VERSION 5.8 ;
BUSBITCHARS "[]" ;
DIVIDERCHAR "/" ;
UNITS
    DATABASE MICRONS 1000 ;
END UNITS

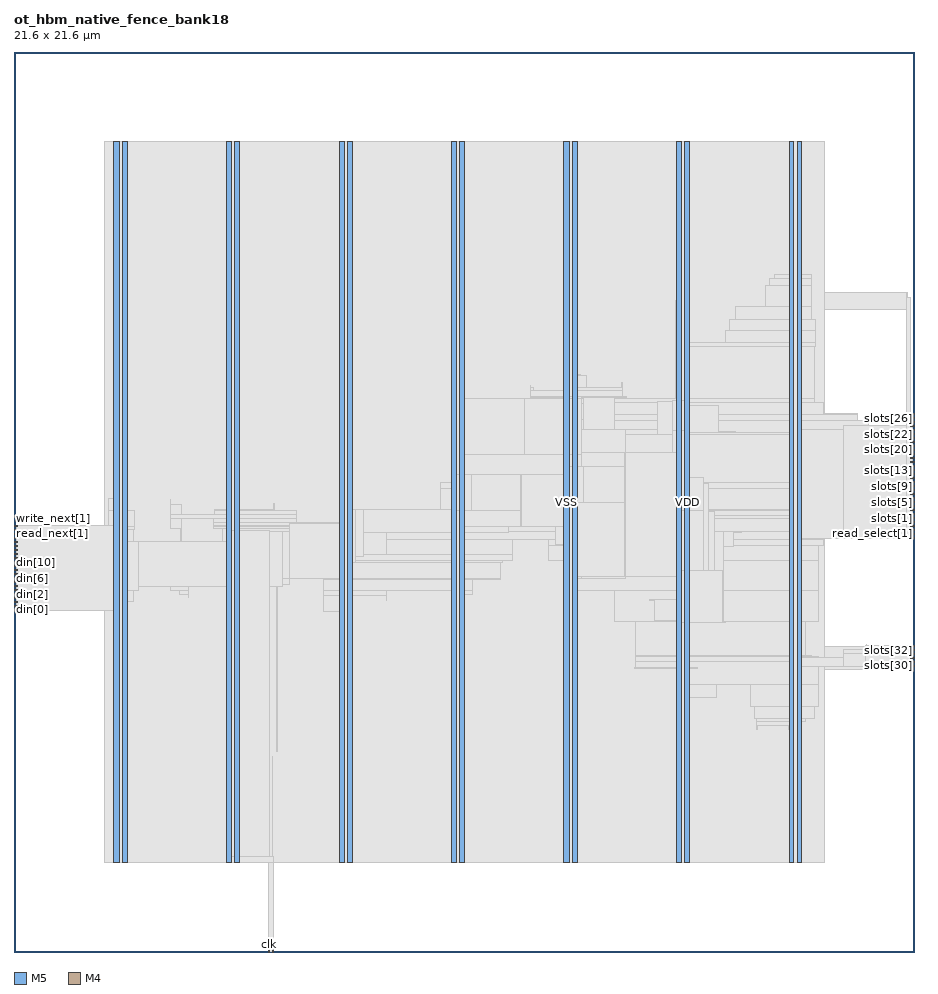
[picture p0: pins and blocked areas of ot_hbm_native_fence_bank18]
MACRO ot_hbm_native_fence_bank18
  FOREIGN ot_hbm_native_fence_bank18 0 0 ;
  CLASS BLOCK ;
  SIZE 21.6 BY 21.6 ;
  PIN clk
    DIRECTION INPUT ;
    USE SIGNAL ;
    PORT
      LAYER M5 ;
        RECT  6.096 0 6.12 0.084 ;
    END
  END clk
  PIN din[0]
    DIRECTION INPUT ;
    USE SIGNAL ;
    PORT
      LAYER M4 ;
        RECT  0 8.208 0.084 8.232 ;
    END
  END din[0]
  PIN din[10]
    DIRECTION INPUT ;
    USE SIGNAL ;
    PORT
      LAYER M4 ;
        RECT  0 9.168 0.084 9.192 ;
    END
  END din[10]
  PIN din[11]
    DIRECTION INPUT ;
    USE SIGNAL ;
    PORT
      LAYER M4 ;
        RECT  0 9.264 0.084 9.288 ;
    END
  END din[11]
  PIN din[12]
    DIRECTION INPUT ;
    USE SIGNAL ;
    PORT
      LAYER M4 ;
        RECT  0 9.36 0.084 9.384 ;
    END
  END din[12]
  PIN din[13]
    DIRECTION INPUT ;
    USE SIGNAL ;
    PORT
      LAYER M4 ;
        RECT  0 9.456 0.084 9.48 ;
    END
  END din[13]
  PIN din[14]
    DIRECTION INPUT ;
    USE SIGNAL ;
    PORT
      LAYER M4 ;
        RECT  0 9.552 0.084 9.576 ;
    END
  END din[14]
  PIN din[15]
    DIRECTION INPUT ;
    USE SIGNAL ;
    PORT
      LAYER M4 ;
        RECT  0 9.648 0.084 9.672 ;
    END
  END din[15]
  PIN din[16]
    DIRECTION INPUT ;
    USE SIGNAL ;
    PORT
      LAYER M4 ;
        RECT  0 9.744 0.084 9.768 ;
    END
  END din[16]
  PIN din[17]
    DIRECTION INPUT ;
    USE SIGNAL ;
    PORT
      LAYER M4 ;
        RECT  0 9.84 0.084 9.864 ;
    END
  END din[17]
  PIN din[1]
    DIRECTION INPUT ;
    USE SIGNAL ;
    PORT
      LAYER M4 ;
        RECT  0 8.304 0.084 8.328 ;
    END
  END din[1]
  PIN din[2]
    DIRECTION INPUT ;
    USE SIGNAL ;
    PORT
      LAYER M4 ;
        RECT  0 8.4 0.084 8.424 ;
    END
  END din[2]
  PIN din[3]
    DIRECTION INPUT ;
    USE SIGNAL ;
    PORT
      LAYER M4 ;
        RECT  0 8.496 0.084 8.52 ;
    END
  END din[3]
  PIN din[4]
    DIRECTION INPUT ;
    USE SIGNAL ;
    PORT
      LAYER M4 ;
        RECT  0 8.592 0.084 8.616 ;
    END
  END din[4]
  PIN din[5]
    DIRECTION INPUT ;
    USE SIGNAL ;
    PORT
      LAYER M4 ;
        RECT  0 8.688 0.084 8.712 ;
    END
  END din[5]
  PIN din[6]
    DIRECTION INPUT ;
    USE SIGNAL ;
    PORT
      LAYER M4 ;
        RECT  0 8.784 0.084 8.808 ;
    END
  END din[6]
  PIN din[7]
    DIRECTION INPUT ;
    USE SIGNAL ;
    PORT
      LAYER M4 ;
        RECT  0 8.88 0.084 8.904 ;
    END
  END din[7]
  PIN din[8]
    DIRECTION INPUT ;
    USE SIGNAL ;
    PORT
      LAYER M4 ;
        RECT  0 8.976 0.084 9 ;
    END
  END din[8]
  PIN din[9]
    DIRECTION INPUT ;
    USE SIGNAL ;
    PORT
      LAYER M4 ;
        RECT  0 9.072 0.084 9.096 ;
    END
  END din[9]
  PIN read_next[0]
    DIRECTION INPUT ;
    USE SIGNAL ;
    PORT
      LAYER M4 ;
        RECT  0 9.936 0.084 9.96 ;
    END
  END read_next[0]
  PIN read_next[1]
    DIRECTION INPUT ;
    USE SIGNAL ;
    PORT
      LAYER M4 ;
        RECT  0 10.032 0.084 10.056 ;
    END
  END read_next[1]
  PIN read_select[0]
    DIRECTION OUTPUT ;
    USE SIGNAL ;
    PORT
      LAYER M4 ;
        RECT  21.516 9.936 21.6 9.96 ;
    END
  END read_select[0]
  PIN read_select[1]
    DIRECTION OUTPUT ;
    USE SIGNAL ;
    PORT
      LAYER M4 ;
        RECT  21.516 10.032 21.6 10.056 ;
    END
  END read_select[1]
  PIN rst_n
    DIRECTION INPUT ;
    USE SIGNAL ;
    PORT
      LAYER M5 ;
        RECT  6.192 0 6.216 0.084 ;
    END
  END rst_n
  PIN slots[0]
    DIRECTION OUTPUT ;
    USE SIGNAL ;
    PORT
      LAYER M4 ;
        RECT  21.516 10.128 21.6 10.152 ;
    END
  END slots[0]
  PIN slots[10]
    DIRECTION OUTPUT ;
    USE SIGNAL ;
    PORT
      LAYER M4 ;
        RECT  21.516 11.088 21.6 11.112 ;
    END
  END slots[10]
  PIN slots[11]
    DIRECTION OUTPUT ;
    USE SIGNAL ;
    PORT
      LAYER M4 ;
        RECT  21.516 11.184 21.6 11.208 ;
    END
  END slots[11]
  PIN slots[12]
    DIRECTION OUTPUT ;
    USE SIGNAL ;
    PORT
      LAYER M4 ;
        RECT  21.516 11.28 21.6 11.304 ;
    END
  END slots[12]
  PIN slots[13]
    DIRECTION OUTPUT ;
    USE SIGNAL ;
    PORT
      LAYER M4 ;
        RECT  21.516 11.376 21.6 11.4 ;
    END
  END slots[13]
  PIN slots[14]
    DIRECTION OUTPUT ;
    USE SIGNAL ;
    PORT
      LAYER M4 ;
        RECT  21.516 11.472 21.6 11.496 ;
    END
  END slots[14]
  PIN slots[15]
    DIRECTION OUTPUT ;
    USE SIGNAL ;
    PORT
      LAYER M4 ;
        RECT  21.516 11.568 21.6 11.592 ;
    END
  END slots[15]
  PIN slots[16]
    DIRECTION OUTPUT ;
    USE SIGNAL ;
    PORT
      LAYER M4 ;
        RECT  21.516 11.664 21.6 11.688 ;
    END
  END slots[16]
  PIN slots[17]
    DIRECTION OUTPUT ;
    USE SIGNAL ;
    PORT
      LAYER M4 ;
        RECT  21.516 11.76 21.6 11.784 ;
    END
  END slots[17]
  PIN slots[18]
    DIRECTION OUTPUT ;
    USE SIGNAL ;
    PORT
      LAYER M4 ;
        RECT  21.516 11.856 21.6 11.88 ;
    END
  END slots[18]
  PIN slots[19]
    DIRECTION OUTPUT ;
    USE SIGNAL ;
    PORT
      LAYER M4 ;
        RECT  21.516 11.952 21.6 11.976 ;
    END
  END slots[19]
  PIN slots[1]
    DIRECTION OUTPUT ;
    USE SIGNAL ;
    PORT
      LAYER M4 ;
        RECT  21.516 10.224 21.6 10.248 ;
    END
  END slots[1]
  PIN slots[20]
    DIRECTION OUTPUT ;
    USE SIGNAL ;
    PORT
      LAYER M4 ;
        RECT  21.516 12.048 21.6 12.072 ;
    END
  END slots[20]
  PIN slots[21]
    DIRECTION OUTPUT ;
    USE SIGNAL ;
    PORT
      LAYER M4 ;
        RECT  21.516 12.144 21.6 12.168 ;
    END
  END slots[21]
  PIN slots[22]
    DIRECTION OUTPUT ;
    USE SIGNAL ;
    PORT
      LAYER M4 ;
        RECT  21.516 12.24 21.6 12.264 ;
    END
  END slots[22]
  PIN slots[23]
    DIRECTION OUTPUT ;
    USE SIGNAL ;
    PORT
      LAYER M4 ;
        RECT  21.516 12.336 21.6 12.36 ;
    END
  END slots[23]
  PIN slots[24]
    DIRECTION OUTPUT ;
    USE SIGNAL ;
    PORT
      LAYER M4 ;
        RECT  21.516 12.432 21.6 12.456 ;
    END
  END slots[24]
  PIN slots[25]
    DIRECTION OUTPUT ;
    USE SIGNAL ;
    PORT
      LAYER M4 ;
        RECT  21.516 12.528 21.6 12.552 ;
    END
  END slots[25]
  PIN slots[26]
    DIRECTION OUTPUT ;
    USE SIGNAL ;
    PORT
      LAYER M4 ;
        RECT  21.516 12.624 21.6 12.648 ;
    END
  END slots[26]
  PIN slots[27]
    DIRECTION OUTPUT ;
    USE SIGNAL ;
    PORT
      LAYER M4 ;
        RECT  21.516 12.72 21.6 12.744 ;
    END
  END slots[27]
  PIN slots[28]
    DIRECTION OUTPUT ;
    USE SIGNAL ;
    PORT
      LAYER M4 ;
        RECT  21.516 12.816 21.6 12.84 ;
    END
  END slots[28]
  PIN slots[29]
    DIRECTION OUTPUT ;
    USE SIGNAL ;
    PORT
      LAYER M4 ;
        RECT  21.516 12.912 21.6 12.936 ;
    END
  END slots[29]
  PIN slots[2]
    DIRECTION OUTPUT ;
    USE SIGNAL ;
    PORT
      LAYER M4 ;
        RECT  21.516 10.32 21.6 10.344 ;
    END
  END slots[2]
  PIN slots[30]
    DIRECTION OUTPUT ;
    USE SIGNAL ;
    PORT
      LAYER M4 ;
        RECT  21.516 6.864 21.6 6.888 ;
    END
  END slots[30]
  PIN slots[31]
    DIRECTION OUTPUT ;
    USE SIGNAL ;
    PORT
      LAYER M4 ;
        RECT  21.516 6.96 21.6 6.984 ;
    END
  END slots[31]
  PIN slots[32]
    DIRECTION OUTPUT ;
    USE SIGNAL ;
    PORT
      LAYER M4 ;
        RECT  21.516 7.056 21.6 7.08 ;
    END
  END slots[32]
  PIN slots[33]
    DIRECTION OUTPUT ;
    USE SIGNAL ;
    PORT
      LAYER M4 ;
        RECT  21.516 7.152 21.6 7.176 ;
    END
  END slots[33]
  PIN slots[34]
    DIRECTION OUTPUT ;
    USE SIGNAL ;
    PORT
      LAYER M4 ;
        RECT  21.516 7.248 21.6 7.272 ;
    END
  END slots[34]
  PIN slots[35]
    DIRECTION OUTPUT ;
    USE SIGNAL ;
    PORT
      LAYER M4 ;
        RECT  21.516 7.344 21.6 7.368 ;
    END
  END slots[35]
  PIN slots[3]
    DIRECTION OUTPUT ;
    USE SIGNAL ;
    PORT
      LAYER M4 ;
        RECT  21.516 10.416 21.6 10.44 ;
    END
  END slots[3]
  PIN slots[4]
    DIRECTION OUTPUT ;
    USE SIGNAL ;
    PORT
      LAYER M4 ;
        RECT  21.516 10.512 21.6 10.536 ;
    END
  END slots[4]
  PIN slots[5]
    DIRECTION OUTPUT ;
    USE SIGNAL ;
    PORT
      LAYER M4 ;
        RECT  21.516 10.608 21.6 10.632 ;
    END
  END slots[5]
  PIN slots[6]
    DIRECTION OUTPUT ;
    USE SIGNAL ;
    PORT
      LAYER M4 ;
        RECT  21.516 10.704 21.6 10.728 ;
    END
  END slots[6]
  PIN slots[7]
    DIRECTION OUTPUT ;
    USE SIGNAL ;
    PORT
      LAYER M4 ;
        RECT  21.516 10.8 21.6 10.824 ;
    END
  END slots[7]
  PIN slots[8]
    DIRECTION OUTPUT ;
    USE SIGNAL ;
    PORT
      LAYER M4 ;
        RECT  21.516 10.896 21.6 10.92 ;
    END
  END slots[8]
  PIN slots[9]
    DIRECTION OUTPUT ;
    USE SIGNAL ;
    PORT
      LAYER M4 ;
        RECT  21.516 10.992 21.6 11.016 ;
    END
  END slots[9]
  PIN write_next[0]
    DIRECTION INPUT ;
    USE SIGNAL ;
    PORT
      LAYER M4 ;
        RECT  0 10.128 0.084 10.152 ;
    END
  END write_next[0]
  PIN write_next[1]
    DIRECTION INPUT ;
    USE SIGNAL ;
    PORT
      LAYER M4 ;
        RECT  0 10.224 0.084 10.248 ;
    END
  END write_next[1]
  PIN VDD
    DIRECTION INOUT ;
    USE POWER ;
    PORT
      LAYER M5 ;
        RECT  18.792 2.151 18.912 19.449 ;
        RECT  16.092 2.151 16.212 19.449 ;
        RECT  13.392 2.151 13.512 19.449 ;
        RECT  10.692 2.151 10.812 19.449 ;
        RECT  7.992 2.151 8.112 19.449 ;
        RECT  5.292 2.151 5.412 19.449 ;
        RECT  2.592 2.151 2.712 19.449 ;
    END
  END VDD
  PIN VSS
    DIRECTION INOUT ;
    USE GROUND ;
    PORT
      LAYER M5 ;
        RECT  18.6 2.137 18.72 19.463 ;
        RECT  15.9 2.137 16.02 19.463 ;
        RECT  13.2 2.137 13.32 19.463 ;
        RECT  10.5 2.137 10.62 19.463 ;
        RECT  7.8 2.137 7.92 19.463 ;
        RECT  5.1 2.137 5.22 19.463 ;
        RECT  2.4 2.137 2.52 19.463 ;
    END
  END VSS
  # OT_OBS_CLOSED layer=M5 d_um=1.536 added=10
  OBS
    LAYER RVTN ;
     RECT  2.16 2.16 19.44 2.295 ;
     RECT  2.16 2.565 19.44 2.835 ;
     RECT  2.16 3.105 19.44 3.375 ;
     RECT  2.16 3.645 19.44 3.915 ;
     RECT  2.16 4.185 19.44 4.455 ;
     RECT  2.16 4.725 19.44 4.995 ;
     RECT  2.16 5.265 19.44 5.535 ;
     RECT  2.16 5.805 19.44 6.075 ;
     RECT  2.16 6.345 19.44 6.615 ;
     RECT  2.16 6.885 19.44 7.155 ;
     RECT  2.16 7.425 19.44 7.695 ;
     RECT  2.16 7.965 19.44 8.235 ;
     RECT  2.16 8.505 19.44 8.775 ;
     RECT  2.16 9.045 19.44 9.315 ;
     RECT  2.16 9.585 19.44 9.855 ;
     RECT  2.16 10.125 19.44 10.395 ;
     RECT  2.16 10.665 19.44 10.935 ;
     RECT  2.16 11.205 19.44 11.475 ;
     RECT  2.16 11.745 19.44 12.015 ;
     RECT  2.16 12.285 19.44 12.555 ;
     RECT  2.16 12.825 19.44 13.095 ;
     RECT  2.16 13.365 19.44 13.635 ;
     RECT  2.16 13.905 19.44 14.175 ;
     RECT  2.16 14.445 19.44 14.715 ;
     RECT  2.16 14.985 19.44 15.255 ;
     RECT  2.16 15.525 19.44 15.795 ;
     RECT  2.16 16.065 19.44 16.335 ;
     RECT  2.16 16.605 19.44 16.875 ;
     RECT  2.16 17.145 19.44 17.415 ;
     RECT  2.16 17.685 19.44 17.955 ;
     RECT  2.16 18.225 19.44 18.495 ;
     RECT  2.16 18.765 19.44 19.035 ;
     RECT  2.16 19.305 19.44 19.44 ;
    LAYER RVTP ;
     RECT  2.16 2.295 19.44 2.565 ;
     RECT  2.16 2.835 19.44 3.105 ;
     RECT  2.16 3.375 19.44 3.645 ;
     RECT  2.16 3.915 19.44 4.185 ;
     RECT  2.16 4.455 19.44 4.725 ;
     RECT  2.16 4.995 19.44 5.265 ;
     RECT  2.16 5.535 19.44 5.805 ;
     RECT  2.16 6.075 19.44 6.345 ;
     RECT  2.16 6.615 19.44 6.885 ;
     RECT  2.16 7.155 19.44 7.425 ;
     RECT  2.16 7.695 19.44 7.965 ;
     RECT  2.16 8.235 19.44 8.505 ;
     RECT  2.16 8.775 19.44 9.045 ;
     RECT  2.16 9.315 19.44 9.585 ;
     RECT  2.16 9.855 19.44 10.125 ;
     RECT  2.16 10.395 19.44 10.665 ;
     RECT  2.16 10.935 19.44 11.205 ;
     RECT  2.16 11.475 19.44 11.745 ;
     RECT  2.16 12.015 19.44 12.285 ;
     RECT  2.16 12.555 19.44 12.825 ;
     RECT  2.16 13.095 19.44 13.365 ;
     RECT  2.16 13.635 19.44 13.905 ;
     RECT  2.16 14.175 19.44 14.445 ;
     RECT  2.16 14.715 19.44 14.985 ;
     RECT  2.16 15.255 19.44 15.525 ;
     RECT  2.16 15.795 19.44 16.065 ;
     RECT  2.16 16.335 19.44 16.605 ;
     RECT  2.16 16.875 19.44 17.145 ;
     RECT  2.16 17.415 19.44 17.685 ;
     RECT  2.16 17.955 19.44 18.225 ;
     RECT  2.16 18.495 19.44 18.765 ;
     RECT  2.16 19.035 19.44 19.305 ;
    LAYER M1 ;
     RECT  2.16 2.151 19.44 19.449 ;
    LAYER M2 ;
     RECT  0.103 9.558 0.203 9.576 ;
     RECT  0.535 9.054 0.671 9.504 ;
     RECT  0.671 9.054 2.16 9.072 ;
     RECT  2.16 2.151 19.44 19.449 ;
     RECT  19.44 10.206 20.255 12.924 ;
     RECT  19.44 6.786 20.507 7.344 ;
     RECT  20.255 10.206 20.507 12.744 ;
     RECT  20.507 6.786 20.543 6.804 ;
     RECT  20.507 10.206 20.543 10.62 ;
     RECT  20.507 11.556 20.543 11.574 ;
     RECT  19.44 15.426 21.443 15.822 ;
     RECT  21.443 15.426 21.479 15.714 ;
     RECT  20.543 10.206 21.515 10.224 ;
     RECT  21.479 15.696 21.515 15.714 ;
    LAYER M3 ;
     RECT  2.415 2.143 2.505 2.413 ;
     RECT  5.115 2.143 5.205 2.413 ;
     RECT  7.815 2.143 7.905 2.413 ;
     RECT  10.515 2.143 10.605 2.413 ;
     RECT  13.215 2.143 13.305 2.413 ;
     RECT  15.915 2.143 16.005 2.413 ;
     RECT  18.615 2.143 18.705 2.413 ;
     RECT  6.192 2.251 6.21 4.685 ;
     RECT  18.615 2.413 18.897 5.341 ;
     RECT  17.82 5.341 17.838 5.431 ;
     RECT  18.576 5.341 18.897 5.431 ;
     RECT  17.82 5.431 18.897 5.539 ;
     RECT  17.82 5.539 18.99 5.611 ;
     RECT  17.784 5.611 19.206 5.881 ;
     RECT  15.915 2.413 16.197 6.115 ;
     RECT  15.915 6.115 16.866 6.421 ;
     RECT  17.676 5.881 19.314 6.421 ;
     RECT  14.904 6.811 14.922 6.961 ;
     RECT  15.915 6.421 19.314 6.961 ;
     RECT  20.52 6.781 20.538 6.989 ;
     RECT  14.904 6.961 19.314 7.085 ;
     RECT  14.904 7.085 19.134 7.115 ;
     RECT  19.908 7.147 20.502 7.259 ;
     RECT  20.448 7.259 20.502 7.349 ;
     RECT  20.448 7.349 20.466 7.373 ;
     RECT  14.904 7.115 18.99 7.933 ;
     RECT  7.815 2.413 8.097 8.167 ;
     RECT  2.415 2.413 2.697 8.203 ;
     RECT  2.304 8.203 2.697 8.401 ;
     RECT  7.416 8.167 8.097 8.545 ;
     RECT  8.928 8.437 8.946 8.545 ;
     RECT  4.176 8.509 4.194 8.581 ;
     RECT  10.515 2.413 10.797 8.581 ;
     RECT  3.96 8.581 4.194 8.671 ;
     RECT  7.416 8.545 8.946 8.671 ;
     RECT  10.515 8.581 10.998 8.671 ;
     RECT  13.215 2.413 13.497 8.671 ;
     RECT  14.4 7.933 19.314 8.671 ;
     RECT  0.144 8.539 0.162 8.683 ;
     RECT  2.304 8.401 2.862 8.683 ;
     RECT  3.744 8.671 4.194 8.771 ;
     RECT  6.3 4.801 6.318 8.779 ;
     RECT  0.144 8.683 0.342 8.813 ;
     RECT  6.3 8.779 6.426 8.815 ;
     RECT  3.888 8.771 4.194 8.851 ;
     RECT  5.115 2.413 5.397 8.851 ;
     RECT  7.416 8.671 10.998 8.941 ;
     RECT  3.888 8.851 5.397 8.969 ;
     RECT  7.416 8.941 11.682 8.969 ;
     RECT  3.996 8.969 5.397 9.005 ;
     RECT  6.3 8.815 6.606 9.013 ;
     RECT  0.288 8.813 0.342 9.049 ;
     RECT  5.004 9.005 5.397 9.247 ;
     RECT  6.3 9.013 7.038 9.247 ;
     RECT  2.304 8.683 2.97 9.293 ;
     RECT  7.815 8.969 11.682 9.355 ;
     RECT  7.815 9.355 11.718 9.391 ;
     RECT  13.215 8.671 19.314 9.391 ;
     RECT  0.288 9.049 0.558 9.451 ;
     RECT  0.288 9.451 0.594 9.481 ;
     RECT  0.288 9.481 0.666 9.533 ;
     RECT  7.815 9.391 11.97 9.533 ;
     RECT  7.815 9.533 8.19 9.545 ;
     RECT  0.288 9.533 0.558 9.553 ;
     RECT  0.108 9.553 0.558 9.581 ;
     RECT  12.816 9.391 19.314 9.751 ;
     RECT  0.108 9.581 0.198 9.773 ;
     RECT  0.18 9.773 0.198 9.821 ;
     RECT  8.928 9.533 11.97 9.895 ;
     RECT  12.816 9.751 19.422 9.895 ;
     RECT  8.928 9.895 19.422 10.085 ;
     RECT  2.304 9.293 2.862 10.129 ;
     RECT  3.996 9.005 4.014 10.165 ;
     RECT  5.004 9.247 7.038 10.165 ;
     RECT  4.788 10.165 7.038 10.201 ;
     RECT  7.815 9.545 8.154 10.201 ;
     RECT  2.304 10.129 2.898 10.219 ;
     RECT  4.788 10.201 8.154 10.229 ;
     RECT  4.788 10.229 8.097 10.301 ;
     RECT  21.492 10.201 21.51 10.349 ;
     RECT  3.744 10.165 4.014 10.399 ;
     RECT  4.788 10.301 6.786 10.399 ;
     RECT  9.468 10.085 19.422 10.411 ;
     RECT  9.468 10.411 19.998 10.471 ;
     RECT  3.744 10.399 6.786 10.499 ;
     RECT  2.268 10.219 2.898 10.589 ;
     RECT  4.824 10.499 6.786 10.589 ;
     RECT  9.468 10.471 20.502 10.597 ;
     RECT  4.824 10.589 6.246 10.625 ;
     RECT  9.468 10.597 20.538 10.625 ;
     RECT  3.744 10.499 4.014 10.733 ;
     RECT  6.228 10.625 6.246 10.769 ;
     RECT  3.744 10.733 3.762 10.859 ;
     RECT  2.268 10.589 2.697 10.895 ;
     RECT  10.224 10.625 20.538 11.117 ;
     RECT  10.224 11.117 19.134 11.273 ;
     RECT  19.908 11.117 20.538 11.597 ;
     RECT  19.908 11.597 20.502 11.851 ;
     RECT  10.515 11.273 19.134 12.427 ;
     RECT  19.872 11.851 20.502 12.427 ;
     RECT  10.515 12.427 20.502 12.479 ;
     RECT  14.4 12.479 20.502 12.749 ;
     RECT  10.515 12.479 13.662 12.785 ;
     RECT  21.492 12.715 21.51 12.811 ;
     RECT  14.4 12.749 20.25 12.893 ;
     RECT  21.456 12.811 21.51 12.907 ;
     RECT  20.232 12.893 20.25 12.929 ;
     RECT  12.096 12.785 13.662 13.163 ;
     RECT  14.4 12.893 19.422 13.199 ;
     RECT  12.204 13.163 13.662 13.289 ;
     RECT  14.4 13.199 19.206 13.289 ;
     RECT  12.384 13.289 13.662 13.297 ;
     RECT  14.4 13.289 14.706 13.297 ;
     RECT  12.384 13.297 14.706 13.325 ;
     RECT  12.384 13.325 14.598 13.469 ;
     RECT  12.384 13.469 12.474 13.559 ;
     RECT  13.215 13.469 14.598 13.559 ;
     RECT  12.384 13.559 12.402 13.595 ;
     RECT  14.58 13.559 14.598 13.667 ;
     RECT  13.215 13.559 13.734 13.829 ;
     RECT  13.215 13.829 13.59 13.865 ;
     RECT  15.876 13.289 19.206 14.521 ;
     RECT  15.876 14.521 19.242 14.639 ;
     RECT  17.064 14.639 19.242 14.909 ;
     RECT  17.172 14.909 19.242 15.179 ;
     RECT  17.316 15.179 19.134 15.485 ;
     RECT  15.876 14.639 16.197 15.629 ;
     RECT  21.42 12.907 21.51 15.719 ;
     RECT  21.42 15.719 21.438 15.827 ;
     RECT  18.036 15.485 19.134 15.989 ;
     RECT  18.144 15.989 19.134 16.169 ;
     RECT  18.252 16.169 19.134 16.259 ;
     RECT  2.415 10.895 2.697 19.187 ;
     RECT  5.115 10.625 5.397 19.187 ;
     RECT  7.815 10.301 8.097 19.187 ;
     RECT  10.515 12.785 10.797 19.187 ;
     RECT  13.215 13.865 13.497 19.187 ;
     RECT  15.915 15.629 16.197 19.187 ;
     RECT  18.615 16.259 18.897 19.187 ;
     RECT  2.415 19.187 2.505 19.457 ;
     RECT  5.115 19.187 5.205 19.457 ;
     RECT  7.815 19.187 7.905 19.457 ;
     RECT  10.515 19.187 10.605 19.457 ;
     RECT  13.215 19.187 13.305 19.457 ;
     RECT  15.915 19.187 16.005 19.457 ;
     RECT  18.615 19.187 18.705 19.457 ;
    LAYER M4 ;
     RECT  0.06 8.208 2.408 10.248 ;
     RECT  2.408 2.148 2.512 19.452 ;
     RECT  2.512 2.418 2.704 19.182 ;
     RECT  2.704 8.544 2.729 9.864 ;
     RECT  2.729 8.688 2.981 9.864 ;
     RECT  2.981 8.784 5.108 9.864 ;
     RECT  5.108 2.148 5.212 19.452 ;
     RECT  5.212 2.256 5.404 19.182 ;
     RECT  5.404 2.256 6.227 2.28 ;
     RECT  5.404 8.784 6.437 10.104 ;
     RECT  6.437 8.976 6.613 10.104 ;
     RECT  6.613 8.976 7.808 10.296 ;
     RECT  7.808 2.148 7.912 19.452 ;
     RECT  7.912 2.418 8.104 19.182 ;
     RECT  8.104 9.36 8.201 10.632 ;
     RECT  8.201 9.504 8.381 10.632 ;
     RECT  8.381 10.08 10.508 10.632 ;
     RECT  10.508 2.148 10.612 19.452 ;
     RECT  10.612 2.418 10.804 19.182 ;
     RECT  10.804 10.08 11.873 11.448 ;
     RECT  11.873 10.224 12.229 11.448 ;
     RECT  12.229 10.224 12.985 11.976 ;
     RECT  12.985 9.792 13.208 11.976 ;
     RECT  12.188 13.248 13.208 13.272 ;
     RECT  13.208 2.148 13.312 19.452 ;
     RECT  13.312 2.418 13.504 19.182 ;
     RECT  13.504 8.976 13.619 13.32 ;
     RECT  13.619 8.976 14.675 12.552 ;
     RECT  14.675 8.976 14.681 11.256 ;
     RECT  15.253 8.448 15.361 8.472 ;
     RECT  14.675 12.432 15.433 12.552 ;
     RECT  14.893 6.816 15.908 6.84 ;
     RECT  15.361 7.968 15.908 8.472 ;
     RECT  14.681 9.792 15.908 11.256 ;
     RECT  15.433 12.432 15.908 13.224 ;
     RECT  15.908 2.148 16.012 19.452 ;
     RECT  16.012 2.418 16.204 19.182 ;
     RECT  16.204 6.816 16.409 6.84 ;
     RECT  16.204 7.92 16.553 11.4 ;
     RECT  16.553 7.92 16.661 11.256 ;
     RECT  16.661 7.92 16.805 10.584 ;
     RECT  16.204 12.48 16.913 13.128 ;
     RECT  16.805 7.92 17.027 10.104 ;
     RECT  17.027 7.92 17.068 7.944 ;
     RECT  17.027 9.744 17.273 10.104 ;
     RECT  16.913 12.48 17.309 12.504 ;
     RECT  17.273 10.08 17.453 10.104 ;
     RECT  18.608 2.148 18.712 19.452 ;
     RECT  18.712 2.418 18.904 19.182 ;
     RECT  18.904 6.864 19.897 7.08 ;
     RECT  18.904 9.936 19.897 12.552 ;
     RECT  19.897 6.864 20.437 7.176 ;
     RECT  19.897 9.936 21.409 12.648 ;
     RECT  20.437 6.864 21.564 7.368 ;
     RECT  21.409 9.936 21.564 12.936 ;
    LAYER M5 ;
     RECT  6.096 0.016 6.216 2.137 ;
     RECT  2.4 2.137 2.52 2.151 ;
     RECT  7.8 2.137 7.92 2.151 ;
     RECT  10.5 2.137 10.62 2.151 ;
     RECT  13.2 2.137 13.32 2.151 ;
     RECT  15.9 2.137 16.02 2.151 ;
     RECT  18.6 2.137 18.72 2.151 ;
     RECT  5.1 2.137 6.216 2.291 ;
     RECT  15.9 2.151 16.212 7.909 ;
     RECT  15.9 7.909 17.016 9.155 ;
     RECT  5.1 2.291 6.12 10.115 ;
     RECT  15.9 9.155 16.536 10.595 ;
     RECT  10.5 2.151 10.812 10.597 ;
     RECT  13.2 2.151 13.512 10.789 ;
     RECT  10.5 10.597 10.968 11.459 ;
     RECT  12.144 10.213 12.168 11.459 ;
     RECT  13.2 10.789 13.656 11.651 ;
     RECT  13.2 11.651 13.608 11.941 ;
     RECT  14.64 9.013 14.664 11.987 ;
     RECT  15.9 10.595 16.212 12.517 ;
     RECT  15.792 12.517 16.212 13.235 ;
     RECT  12.24 11.941 13.608 13.283 ;
     RECT  13.2 13.283 13.608 13.331 ;
     RECT  2.4 2.151 2.712 19.449 ;
     RECT  5.1 10.115 5.412 19.449 ;
     RECT  7.8 2.151 8.112 19.449 ;
     RECT  10.5 11.459 10.812 19.449 ;
     RECT  13.2 13.331 13.512 19.449 ;
     RECT  15.9 13.235 16.212 19.449 ;
     RECT  18.6 2.151 18.912 19.449 ;
     RECT  2.4 19.449 2.52 19.463 ;
     RECT  5.1 19.449 5.22 19.463 ;
     RECT  7.8 19.449 7.92 19.463 ;
     RECT  10.5 19.449 10.62 19.463 ;
     RECT  13.2 19.449 13.32 19.463 ;
     RECT  15.9 19.449 16.02 19.463 ;
     RECT  18.6 19.449 18.72 19.463 ;
     RECT  13.512 9.013 14.64 10.789 ;
     RECT  14.664 9.013 15.9 11.987 ;
     RECT  10.812 10.213 12.144 10.597 ;
     RECT  12.168 10.213 13.2 11.459 ;
     RECT  10.968 10.597 12.144 11.459 ;
     RECT  13.656 10.789 14.64 11.651 ;
     RECT  10.812 11.459 13.2 11.941 ;
     RECT  13.608 11.651 14.64 11.987 ;
     RECT  10.812 11.941 12.24 13.283 ;
     RECT  15.792 11.987 15.9 12.517 ;
  END
END ot_hbm_native_fence_bank18
END LIBRARY
